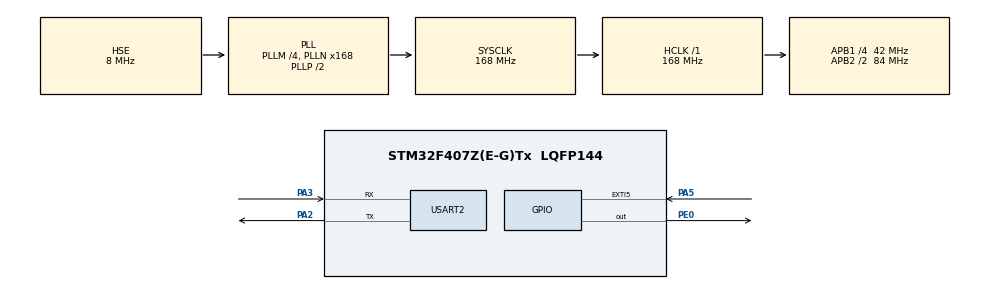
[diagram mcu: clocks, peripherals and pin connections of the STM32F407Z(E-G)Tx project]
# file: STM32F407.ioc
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Mcu.Family=STM32F4
Mcu.Name=STM32F407Z(E-G)Tx
Mcu.Package=LQFP144
NVIC.EXTI9_5_IRQn=true\:0\:0\:false\:false\:true\:true\:true
NVIC.PriorityGroup=NVIC_PRIORITYGROUP_4
NVIC.TIM6_DAC_IRQn=true\:0\:0\:false\:false\:true\:true\:true
PA13.Mode=Trace_Asynchronous_SW
PA13.Signal=SYS_JTMS-SWDIO
PA14.Mode=Trace_Asynchronous_SW
PA14.Signal=SYS_JTCK-SWCLK
PA2.Mode=Asynchronous
PA2.Signal=USART2_TX
PA3.Mode=Asynchronous
PA3.Signal=USART2_RX
PA5.GPIO_ModeDefaultEXTI=GPIO_MODE_IT_RISING_FALLING
PA5.GPIO_PuPd=GPIO_NOPULL
PA5.Signal=GPXTI5
PB3.Mode=Trace_Asynchronous_SW
PB3.Signal=SYS_JTDO-SWO
PC14-OSC32_IN.Mode=LSE-External-Oscillator
PC14-OSC32_IN.Signal=RCC_OSC32_IN
PC15-OSC32_OUT.Mode=LSE-External-Oscillator
PC15-OSC32_OUT.Signal=RCC_OSC32_OUT
PE0.PinState=GPIO_PIN_SET
PE0.Signal=GPIO_Output
PH0-OSC_IN.Mode=HSE-External-Oscillator
PH0-OSC_IN.Signal=RCC_OSC_IN
PH1-OSC_OUT.Mode=HSE-External-Oscillator
PH1-OSC_OUT.Signal=RCC_OSC_OUT
ProjectManager.HeapSize=0x200
ProjectManager.StackSize=0x400
ProjectManager.TargetToolchain=STM32CubeIDE
RCC.48MHZClocksFreq_Value=84000000
RCC.AHBFreq_Value=168000000
RCC.APB1CLKDivider=RCC_HCLK_DIV4
RCC.APB1Freq_Value=42000000
RCC.APB1TimFreq_Value=84000000
RCC.APB2CLKDivider=RCC_HCLK_DIV2
RCC.APB2Freq_Value=84000000
RCC.APB2TimFreq_Value=168000000
RCC.CortexFreq_Value=168000000
RCC.HCLKFreq_Value=168000000
RCC.HSE_VALUE=8000000
RCC.HSI_VALUE=16000000
RCC.PLLM=4
RCC.PLLN=168
RCC.PLLSourceVirtual=RCC_PLLSOURCE_HSE
RCC.SYSCLKFreq_VALUE=168000000
RCC.SYSCLKSource=RCC_SYSCLKSOURCE_PLLCLK
RCC.VCOOutputFreq_Value=336000000
TIM6.Period=125
TIM6.Prescaler=83
TIM6.TIM_MasterOutputTrigger=TIM_TRGO_RESET
TIM7.Period=65535
TIM7.Prescaler=83
USART2.VirtualMode=VM_ASYNC
VP_TIM6_VS_ClockSourceINT.Mode=Enable_Timer
VP_TIM7_VS_ClockSourceINT.Mode=Enable_Timer
board=custom

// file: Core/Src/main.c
/* USER CODE BEGIN Header */
/**
  ******************************************************************************
  * @file           : main.c
  * @brief          : Main program body
  ******************************************************************************
  * @attention
  *
  * <h2><center>&copy; Copyright (c) 2020 STMicroelectronics.
  * All rights reserved.</center></h2>
  *
  * This software component is licensed by ST under BSD 3-Clause license,
  * the "License"; You may not use this file except in compliance with the
  * License. You may obtain a copy of the License at:
  *                        opensource.org/licenses/BSD-3-Clause
  *
  ******************************************************************************
  */
/* USER CODE END Header */

#include "main.h"

/* USER CODE BEGIN Includes */
#include "ManchesterCode.h"
/* USER CODE END Includes */

/* USER CODE BEGIN PD */

#ifdef __GNUC__
#define PUTCHAR_PROTOTYPE int __io_putchar(int ch)
#else
#define PUTCHAR_PROTOTYPE int fputc(int ch, FILE *f)
#endif

/* USER CODE END PD */

TIM_HandleTypeDef htim6;
TIM_HandleTypeDef htim7;

UART_HandleTypeDef huart2;

void SystemClock_Config(void);
static void MX_GPIO_Init(void);
static void MX_TIM7_Init(void);
static void MX_TIM6_Init(void);
static void MX_USART2_UART_Init(void);
/* USER CODE BEGIN PFP */
void delay_us(uint16_t us);

/* USER CODE END PFP */

int main(void)
{

  /* MCU Configuration--------------------------------------------------------*/

  /* Reset of all peripherals, Initializes the Flash interface and the Systick. */
  HAL_Init();

  /* Configure the system clock */
  SystemClock_Config();

  /* Initialize all configured peripherals */
  MX_GPIO_Init();
  MX_TIM7_Init();
  MX_TIM6_Init();
  MX_USART2_UART_Init();
  /* USER CODE BEGIN 2 */
  HAL_GPIO_WritePin(GPIOF, GPIO_PIN_9, GPIO_PIN_RESET);
  //HAL_GPIO_WritePin(GPIOE, GPIO_PIN_0, GPIO_PIN_SET);
  HAL_TIM_Base_Start_IT(&htim6);
  HAL_Delay(1000);
  uint8_t dataSend[25] = {0X88, 0x33, 0x00, 0x55, 0x50, 0x60, 0x70, 0x80, 0x90, 0xa0, 0x30, 0x30, 0x30, 0x31, 0x01,
  							  0x00, 0x00, 0x00, 0x00, 0x00, 0xBB, 0xCC, 0xDD, 0xEE, 0xAA};
  uint8_t dataLens = 25;
  //DiffManchester_SendData   (dataSend, 25);

  //uint8_t TMR1H = 0x07;
  //uint8_t TMR1L = 0xD9;
  //uint16_t timval = (TMR1H<<8) | (TMR1L);
  //timval = timval /10;

  /* USER CODE END 2 */

  /* Infinite loop */
  while (1)
  {

    /* USER CODE BEGIN 3 */

	//HAL_Delay(500);
	uint8_t data[25];
	//uint8_t dataSend[25] = {0X00, 0x37, 0x33, 0x30, 0x30, 0x30, 0x30, 0x30, 0x30, 0x30, 0x30, 0x30, 0x30, 0x31, 0x01,
	//						  0x00, 0x00, 0x00, 0x00, 0x00, 0x00, 0x00, 0x00, 0xEE, 0xAA};

	DiffManchester_SendData   (dataSend, 25);
	//HAL_Delay(10);
	DiffManchester_WaitForRead(  );

	if( 0 == DiffManchester_GetData( data, dataLens ))
	{
		//DiffManchester_SendData   (data, 25);
		for( uint8_t j=0; j<dataLens; j++ )
			printf( "%x ", data[j] );
		printf( "\r\n");
	}
    else
    {
    	printf("error\r\n");
    }

	//HAL_Delay(5000);

  }
  /* USER CODE END 3 */
}

void SystemClock_Config(void)
{
  RCC_OscInitTypeDef RCC_OscInitStruct = {0};
  RCC_ClkInitTypeDef RCC_ClkInitStruct = {0};

  /** Configure the main internal regulator output voltage
  */
  __HAL_RCC_PWR_CLK_ENABLE();
  __HAL_PWR_VOLTAGESCALING_CONFIG(PWR_REGULATOR_VOLTAGE_SCALE1);
  /** Initializes the CPU, AHB and APB busses clocks
  */
  RCC_OscInitStruct.OscillatorType = RCC_OSCILLATORTYPE_HSE;
  RCC_OscInitStruct.HSEState = RCC_HSE_ON;
  RCC_OscInitStruct.PLL.PLLState = RCC_PLL_ON;
  RCC_OscInitStruct.PLL.PLLSource = RCC_PLLSOURCE_HSE;
  RCC_OscInitStruct.PLL.PLLM = 4;
  RCC_OscInitStruct.PLL.PLLN = 168;
  RCC_OscInitStruct.PLL.PLLP = RCC_PLLP_DIV2;
  RCC_OscInitStruct.PLL.PLLQ = 4;
  if (HAL_RCC_OscConfig(&RCC_OscInitStruct) != HAL_OK)
  {
    Error_Handler();
  }
  /** Initializes the CPU, AHB and APB busses clocks
  */
  RCC_ClkInitStruct.ClockType = RCC_CLOCKTYPE_HCLK|RCC_CLOCKTYPE_SYSCLK
                              |RCC_CLOCKTYPE_PCLK1|RCC_CLOCKTYPE_PCLK2;
  RCC_ClkInitStruct.SYSCLKSource = RCC_SYSCLKSOURCE_PLLCLK;
  RCC_ClkInitStruct.AHBCLKDivider = RCC_SYSCLK_DIV1;
  RCC_ClkInitStruct.APB1CLKDivider = RCC_HCLK_DIV4;
  RCC_ClkInitStruct.APB2CLKDivider = RCC_HCLK_DIV2;

  if (HAL_RCC_ClockConfig(&RCC_ClkInitStruct, FLASH_LATENCY_5) != HAL_OK)
  {
    Error_Handler();
  }
}

static void MX_TIM6_Init(void)
{

  TIM_MasterConfigTypeDef sMasterConfig = {0};

  htim6.Instance = TIM6;
  htim6.Init.Prescaler = 83;
  htim6.Init.CounterMode = TIM_COUNTERMODE_UP;
  htim6.Init.Period = 130;
  htim6.Init.AutoReloadPreload = TIM_AUTORELOAD_PRELOAD_DISABLE;
  if (HAL_TIM_Base_Init(&htim6) != HAL_OK)
  {
    Error_Handler();
  }
  sMasterConfig.MasterOutputTrigger = TIM_TRGO_RESET;
  sMasterConfig.MasterSlaveMode = TIM_MASTERSLAVEMODE_DISABLE;
  if (HAL_TIMEx_MasterConfigSynchronization(&htim6, &sMasterConfig) != HAL_OK)
  {
    Error_Handler();
  }

}

static void MX_TIM7_Init(void)
{

  TIM_MasterConfigTypeDef sMasterConfig = {0};

  htim7.Instance = TIM7;
  htim7.Init.Prescaler = 83;
  htim7.Init.CounterMode = TIM_COUNTERMODE_UP;
  htim7.Init.Period = 65535;
  htim7.Init.AutoReloadPreload = TIM_AUTORELOAD_PRELOAD_DISABLE;
  if (HAL_TIM_Base_Init(&htim7) != HAL_OK)
  {
    Error_Handler();
  }
  sMasterConfig.MasterOutputTrigger = TIM_TRGO_RESET;
  sMasterConfig.MasterSlaveMode = TIM_MASTERSLAVEMODE_DISABLE;
  if (HAL_TIMEx_MasterConfigSynchronization(&htim7, &sMasterConfig) != HAL_OK)
  {
    Error_Handler();
  }

}

static void MX_USART2_UART_Init(void)
{

  huart2.Instance = USART2;
  huart2.Init.BaudRate = 115200;
  huart2.Init.WordLength = UART_WORDLENGTH_8B;
  huart2.Init.StopBits = UART_STOPBITS_1;
  huart2.Init.Parity = UART_PARITY_NONE;
  huart2.Init.Mode = UART_MODE_TX_RX;
  huart2.Init.HwFlowCtl = UART_HWCONTROL_NONE;
  huart2.Init.OverSampling = UART_OVERSAMPLING_16;
  if (HAL_UART_Init(&huart2) != HAL_OK)
  {
    Error_Handler();
  }

}

static void MX_GPIO_Init(void)
{
  GPIO_InitTypeDef GPIO_InitStruct = {0};

  /* GPIO Ports Clock Enable */
  __HAL_RCC_GPIOE_CLK_ENABLE();
  __HAL_RCC_GPIOC_CLK_ENABLE();
  __HAL_RCC_GPIOF_CLK_ENABLE();
  __HAL_RCC_GPIOH_CLK_ENABLE();
  __HAL_RCC_GPIOA_CLK_ENABLE();
  __HAL_RCC_GPIOB_CLK_ENABLE();

  /*Configure GPIO pin Output Level */
  HAL_GPIO_WritePin(GPIOE, GPIO_PIN_4, GPIO_PIN_RESET);

  /*Configure GPIO pin Output Level */
  HAL_GPIO_WritePin(GPIOE, GPIO_PIN_0, GPIO_PIN_SET);

  /*Configure GPIO pins : PE4 PE0 */
  GPIO_InitStruct.Pin = GPIO_PIN_4|GPIO_PIN_0;
  GPIO_InitStruct.Mode = GPIO_MODE_OUTPUT_PP;
  GPIO_InitStruct.Pull = GPIO_NOPULL;
  GPIO_InitStruct.Speed = GPIO_SPEED_FREQ_LOW;
  HAL_GPIO_Init(GPIOE, &GPIO_InitStruct);

  /*Configure GPIO pin : PF0 */
  GPIO_InitStruct.Pin = GPIO_PIN_0;
  GPIO_InitStruct.Mode = GPIO_MODE_INPUT;
  GPIO_InitStruct.Pull = GPIO_NOPULL;
  HAL_GPIO_Init(GPIOF, &GPIO_InitStruct);

  /*Configure GPIO pin : PA5 */
  GPIO_InitStruct.Pin = GPIO_PIN_5;
  GPIO_InitStruct.Mode = GPIO_MODE_IT_RISING_FALLING;
  GPIO_InitStruct.Pull = GPIO_NOPULL;
  HAL_GPIO_Init(GPIOA, &GPIO_InitStruct);

  /* EXTI interrupt init*/
  HAL_NVIC_SetPriority(EXTI9_5_IRQn, 0, 0);
  HAL_NVIC_EnableIRQ(EXTI9_5_IRQn);

}

/* USER CODE BEGIN 4 */
PUTCHAR_PROTOTYPE
{
	HAL_UART_Transmit(&huart2, (uint8_t*)&ch,1,HAL_MAX_DELAY);
    return ch;
}

void delay_us(uint16_t us)
{
	uint16_t differ=0xffff-us-5;

	HAL_TIM_Base_Start(&htim7);
	__HAL_TIM_SetCounter(&htim7,differ);
	while(differ < 0xffff-5)
	{
		differ = __HAL_TIM_GetCounter(&htim7);
	}
	HAL_TIM_Base_Stop(&htim7);
}

int8_t count = 0;

void HAL_TIM_PeriodElapsedCallback(TIM_HandleTypeDef *htim)
{
	if(htim6.Instance == htim->Instance)
	{
		//HAL_GPIO_TogglePin( GPIOE,GPIO_PIN_4);
		DiffManchester_ReadBit(  );

		if (! count--) __HAL_TIM_DISABLE_IT(&htim6, TIM_IT_UPDATE);

	}
}

void HAL_GPIO_EXTI_Callback(uint16_t GPIO_Pin)
{
  if(GPIO_Pin == GPIO_PIN_5)
  {

	  DiffManchester_EnableRead( 1 );
	  if( IS_IOSET(RX_PORT,RX_PIN) ) TIM6->CNT = 90;
	  else                           TIM6->CNT = 35;

	  count = 3;
	  HAL_TIM_Base_Start_IT(&htim6);
	  __HAL_TIM_CLEAR_FLAG(&htim6,TIM_FLAG_UPDATE);
	  //HAL_GPIO_TogglePin( GPIOE,GPIO_PIN_4);

   }
}
/* USER CODE END 4 */

void Error_Handler(void)
{
}

/************************ (C) COPYRIGHT STMicroelectronics *****END OF FILE****/
